VERSION 5.8 ;
BUSBITCHARS "[]" ;
DIVIDERCHAR "/" ;
UNITS
    DATABASE MICRONS 1000 ;
END UNITS

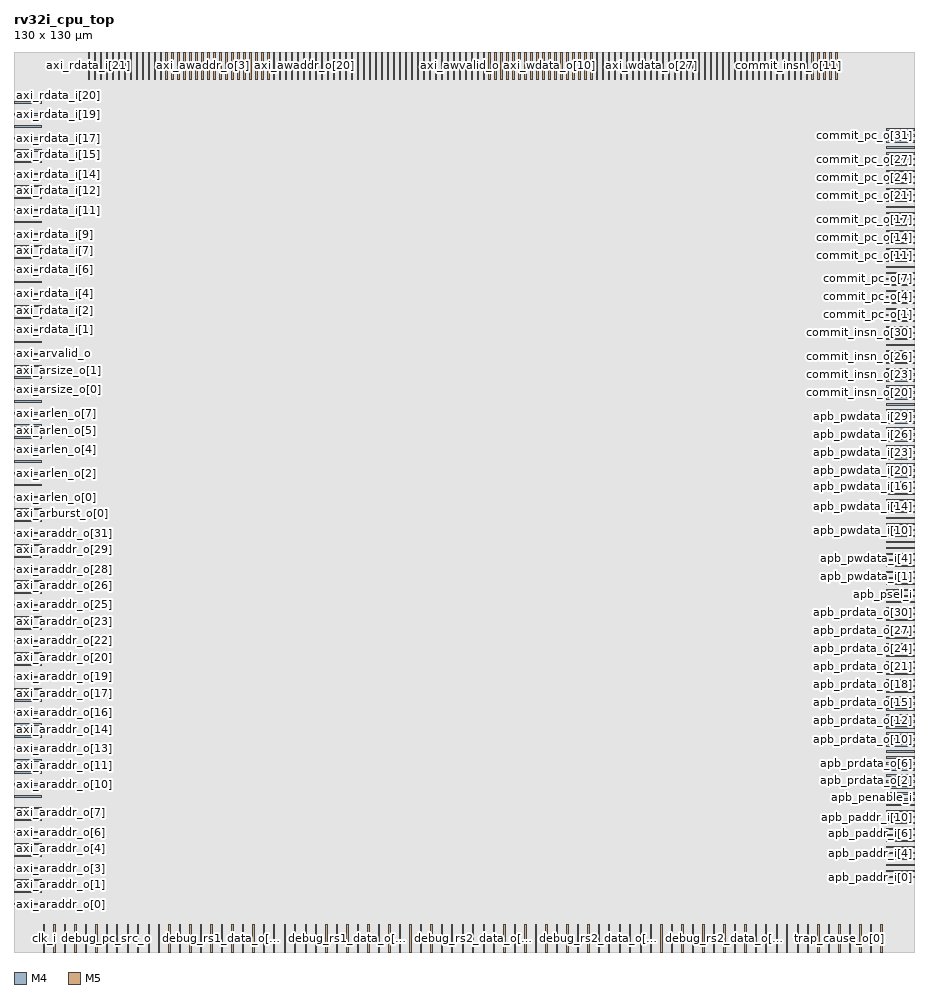
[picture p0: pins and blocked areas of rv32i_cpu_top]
MACRO rv32i_cpu_top
  FOREIGN rv32i_cpu_top 0 0 ;
  CLASS BLOCK ;
  SIZE 130 BY 130 ;
  PIN VDD
    USE POWER ;
    DIRECTION INOUT ;
  END VDD
  PIN VSS
    USE GROUND ;
    DIRECTION INOUT ;
  END VSS
  PIN apb_paddr_i[0]
    DIRECTION INPUT ;
    USE SIGNAL ;
    PORT
      LAYER M4 ;
        RECT  126 10.722 130 10.914 ;
    END
  END apb_paddr_i[0]
  PIN apb_paddr_i[10]
    DIRECTION INPUT ;
    USE SIGNAL ;
    PORT
      LAYER M4 ;
        RECT  126 19.362 130 19.554 ;
    END
  END apb_paddr_i[10]
  PIN apb_paddr_i[11]
    DIRECTION INPUT ;
    USE SIGNAL ;
    PORT
      LAYER M4 ;
        RECT  126 20.226 130 20.418 ;
    END
  END apb_paddr_i[11]
  PIN apb_paddr_i[1]
    DIRECTION INPUT ;
    USE SIGNAL ;
    PORT
      LAYER M4 ;
        RECT  126 11.586 130 11.778 ;
    END
  END apb_paddr_i[1]
  PIN apb_paddr_i[2]
    DIRECTION INPUT ;
    USE SIGNAL ;
    PORT
      LAYER M4 ;
        RECT  126 12.45 130 12.642 ;
    END
  END apb_paddr_i[2]
  PIN apb_paddr_i[3]
    DIRECTION INPUT ;
    USE SIGNAL ;
    PORT
      LAYER M4 ;
        RECT  126 13.314 130 13.506 ;
    END
  END apb_paddr_i[3]
  PIN apb_paddr_i[4]
    DIRECTION INPUT ;
    USE SIGNAL ;
    PORT
      LAYER M4 ;
        RECT  126 14.178 130 14.37 ;
    END
  END apb_paddr_i[4]
  PIN apb_paddr_i[5]
    DIRECTION INPUT ;
    USE SIGNAL ;
    PORT
      LAYER M4 ;
        RECT  126 15.042 130 15.234 ;
    END
  END apb_paddr_i[5]
  PIN apb_paddr_i[6]
    DIRECTION INPUT ;
    USE SIGNAL ;
    PORT
      LAYER M4 ;
        RECT  126 15.906 130 16.098 ;
    END
  END apb_paddr_i[6]
  PIN apb_paddr_i[7]
    DIRECTION INPUT ;
    USE SIGNAL ;
    PORT
      LAYER M4 ;
        RECT  126 16.77 130 16.962 ;
    END
  END apb_paddr_i[7]
  PIN apb_paddr_i[8]
    DIRECTION INPUT ;
    USE SIGNAL ;
    PORT
      LAYER M4 ;
        RECT  126 17.634 130 17.826 ;
    END
  END apb_paddr_i[8]
  PIN apb_paddr_i[9]
    DIRECTION INPUT ;
    USE SIGNAL ;
    PORT
      LAYER M4 ;
        RECT  126 18.498 130 18.69 ;
    END
  END apb_paddr_i[9]
  PIN apb_penable_i
    DIRECTION INPUT ;
    USE SIGNAL ;
    PORT
      LAYER M4 ;
        RECT  126 21.09 130 21.282 ;
    END
  END apb_penable_i
  PIN apb_prdata_o[0]
    DIRECTION OUTPUT ;
    USE SIGNAL ;
    PORT
      LAYER M4 ;
        RECT  126 21.954 130 22.146 ;
    END
  END apb_prdata_o[0]
  PIN apb_prdata_o[10]
    DIRECTION OUTPUT ;
    USE SIGNAL ;
    PORT
      LAYER M4 ;
        RECT  126 30.594 130 30.786 ;
    END
  END apb_prdata_o[10]
  PIN apb_prdata_o[11]
    DIRECTION OUTPUT ;
    USE SIGNAL ;
    PORT
      LAYER M4 ;
        RECT  126 31.458 130 31.65 ;
    END
  END apb_prdata_o[11]
  PIN apb_prdata_o[12]
    DIRECTION OUTPUT ;
    USE SIGNAL ;
    PORT
      LAYER M4 ;
        RECT  126 32.322 130 32.514 ;
    END
  END apb_prdata_o[12]
  PIN apb_prdata_o[13]
    DIRECTION OUTPUT ;
    USE SIGNAL ;
    PORT
      LAYER M4 ;
        RECT  126 33.186 130 33.378 ;
    END
  END apb_prdata_o[13]
  PIN apb_prdata_o[14]
    DIRECTION OUTPUT ;
    USE SIGNAL ;
    PORT
      LAYER M4 ;
        RECT  126 34.05 130 34.242 ;
    END
  END apb_prdata_o[14]
  PIN apb_prdata_o[15]
    DIRECTION OUTPUT ;
    USE SIGNAL ;
    PORT
      LAYER M4 ;
        RECT  126 34.914 130 35.106 ;
    END
  END apb_prdata_o[15]
  PIN apb_prdata_o[16]
    DIRECTION OUTPUT ;
    USE SIGNAL ;
    PORT
      LAYER M4 ;
        RECT  126 35.778 130 35.97 ;
    END
  END apb_prdata_o[16]
  PIN apb_prdata_o[17]
    DIRECTION OUTPUT ;
    USE SIGNAL ;
    PORT
      LAYER M4 ;
        RECT  126 36.642 130 36.834 ;
    END
  END apb_prdata_o[17]
  PIN apb_prdata_o[18]
    DIRECTION OUTPUT ;
    USE SIGNAL ;
    PORT
      LAYER M4 ;
        RECT  126 37.506 130 37.698 ;
    END
  END apb_prdata_o[18]
  PIN apb_prdata_o[19]
    DIRECTION OUTPUT ;
    USE SIGNAL ;
    PORT
      LAYER M4 ;
        RECT  126 38.37 130 38.562 ;
    END
  END apb_prdata_o[19]
  PIN apb_prdata_o[1]
    DIRECTION OUTPUT ;
    USE SIGNAL ;
    PORT
      LAYER M4 ;
        RECT  126 22.818 130 23.01 ;
    END
  END apb_prdata_o[1]
  PIN apb_prdata_o[20]
    DIRECTION OUTPUT ;
    USE SIGNAL ;
    PORT
      LAYER M4 ;
        RECT  126 39.234 130 39.426 ;
    END
  END apb_prdata_o[20]
  PIN apb_prdata_o[21]
    DIRECTION OUTPUT ;
    USE SIGNAL ;
    PORT
      LAYER M4 ;
        RECT  126 40.098 130 40.29 ;
    END
  END apb_prdata_o[21]
  PIN apb_prdata_o[22]
    DIRECTION OUTPUT ;
    USE SIGNAL ;
    PORT
      LAYER M4 ;
        RECT  126 40.962 130 41.154 ;
    END
  END apb_prdata_o[22]
  PIN apb_prdata_o[23]
    DIRECTION OUTPUT ;
    USE SIGNAL ;
    PORT
      LAYER M4 ;
        RECT  126 41.826 130 42.018 ;
    END
  END apb_prdata_o[23]
  PIN apb_prdata_o[24]
    DIRECTION OUTPUT ;
    USE SIGNAL ;
    PORT
      LAYER M4 ;
        RECT  126 42.69 130 42.882 ;
    END
  END apb_prdata_o[24]
  PIN apb_prdata_o[25]
    DIRECTION OUTPUT ;
    USE SIGNAL ;
    PORT
      LAYER M4 ;
        RECT  126 43.554 130 43.746 ;
    END
  END apb_prdata_o[25]
  PIN apb_prdata_o[26]
    DIRECTION OUTPUT ;
    USE SIGNAL ;
    PORT
      LAYER M4 ;
        RECT  126 44.418 130 44.61 ;
    END
  END apb_prdata_o[26]
  PIN apb_prdata_o[27]
    DIRECTION OUTPUT ;
    USE SIGNAL ;
    PORT
      LAYER M4 ;
        RECT  126 45.282 130 45.474 ;
    END
  END apb_prdata_o[27]
  PIN apb_prdata_o[28]
    DIRECTION OUTPUT ;
    USE SIGNAL ;
    PORT
      LAYER M4 ;
        RECT  126 46.146 130 46.338 ;
    END
  END apb_prdata_o[28]
  PIN apb_prdata_o[29]
    DIRECTION OUTPUT ;
    USE SIGNAL ;
    PORT
      LAYER M4 ;
        RECT  126 47.01 130 47.202 ;
    END
  END apb_prdata_o[29]
  PIN apb_prdata_o[2]
    DIRECTION OUTPUT ;
    USE SIGNAL ;
    PORT
      LAYER M4 ;
        RECT  126 23.682 130 23.874 ;
    END
  END apb_prdata_o[2]
  PIN apb_prdata_o[30]
    DIRECTION OUTPUT ;
    USE SIGNAL ;
    PORT
      LAYER M4 ;
        RECT  126 47.874 130 48.066 ;
    END
  END apb_prdata_o[30]
  PIN apb_prdata_o[31]
    DIRECTION OUTPUT ;
    USE SIGNAL ;
    PORT
      LAYER M4 ;
        RECT  126 48.738 130 48.93 ;
    END
  END apb_prdata_o[31]
  PIN apb_prdata_o[3]
    DIRECTION OUTPUT ;
    USE SIGNAL ;
    PORT
      LAYER M4 ;
        RECT  126 24.546 130 24.738 ;
    END
  END apb_prdata_o[3]
  PIN apb_prdata_o[4]
    DIRECTION OUTPUT ;
    USE SIGNAL ;
    PORT
      LAYER M4 ;
        RECT  126 25.41 130 25.602 ;
    END
  END apb_prdata_o[4]
  PIN apb_prdata_o[5]
    DIRECTION OUTPUT ;
    USE SIGNAL ;
    PORT
      LAYER M4 ;
        RECT  126 26.274 130 26.466 ;
    END
  END apb_prdata_o[5]
  PIN apb_prdata_o[6]
    DIRECTION OUTPUT ;
    USE SIGNAL ;
    PORT
      LAYER M4 ;
        RECT  126 27.138 130 27.33 ;
    END
  END apb_prdata_o[6]
  PIN apb_prdata_o[7]
    DIRECTION OUTPUT ;
    USE SIGNAL ;
    PORT
      LAYER M4 ;
        RECT  126 28.002 130 28.194 ;
    END
  END apb_prdata_o[7]
  PIN apb_prdata_o[8]
    DIRECTION OUTPUT ;
    USE SIGNAL ;
    PORT
      LAYER M4 ;
        RECT  126 28.866 130 29.058 ;
    END
  END apb_prdata_o[8]
  PIN apb_prdata_o[9]
    DIRECTION OUTPUT ;
    USE SIGNAL ;
    PORT
      LAYER M4 ;
        RECT  126 29.73 130 29.922 ;
    END
  END apb_prdata_o[9]
  PIN apb_pready_o
    DIRECTION OUTPUT ;
    USE SIGNAL ;
    PORT
      LAYER M4 ;
        RECT  126 49.602 130 49.794 ;
    END
  END apb_pready_o
  PIN apb_psel_i
    DIRECTION INPUT ;
    USE SIGNAL ;
    PORT
      LAYER M4 ;
        RECT  126 50.466 130 50.658 ;
    END
  END apb_psel_i
  PIN apb_pslverr_o
    DIRECTION OUTPUT ;
    USE SIGNAL ;
    PORT
      LAYER M4 ;
        RECT  126 51.33 130 51.522 ;
    END
  END apb_pslverr_o
  PIN apb_pwdata_i[0]
    DIRECTION INPUT ;
    USE SIGNAL ;
    PORT
      LAYER M4 ;
        RECT  126 52.194 130 52.386 ;
    END
  END apb_pwdata_i[0]
  PIN apb_pwdata_i[10]
    DIRECTION INPUT ;
    USE SIGNAL ;
    PORT
      LAYER M4 ;
        RECT  126 60.834 130 61.026 ;
    END
  END apb_pwdata_i[10]
  PIN apb_pwdata_i[11]
    DIRECTION INPUT ;
    USE SIGNAL ;
    PORT
      LAYER M4 ;
        RECT  126 61.698 130 61.89 ;
    END
  END apb_pwdata_i[11]
  PIN apb_pwdata_i[12]
    DIRECTION INPUT ;
    USE SIGNAL ;
    PORT
      LAYER M4 ;
        RECT  126 62.562 130 62.754 ;
    END
  END apb_pwdata_i[12]
  PIN apb_pwdata_i[13]
    DIRECTION INPUT ;
    USE SIGNAL ;
    PORT
      LAYER M4 ;
        RECT  126 63.426 130 63.618 ;
    END
  END apb_pwdata_i[13]
  PIN apb_pwdata_i[14]
    DIRECTION INPUT ;
    USE SIGNAL ;
    PORT
      LAYER M4 ;
        RECT  126 64.29 130 64.482 ;
    END
  END apb_pwdata_i[14]
  PIN apb_pwdata_i[15]
    DIRECTION INPUT ;
    USE SIGNAL ;
    PORT
      LAYER M4 ;
        RECT  126 65.154 130 65.346 ;
    END
  END apb_pwdata_i[15]
  PIN apb_pwdata_i[16]
    DIRECTION INPUT ;
    USE SIGNAL ;
    PORT
      LAYER M4 ;
        RECT  126 66.018 130 66.21 ;
    END
  END apb_pwdata_i[16]
  PIN apb_pwdata_i[17]
    DIRECTION INPUT ;
    USE SIGNAL ;
    PORT
      LAYER M4 ;
        RECT  126 66.882 130 67.074 ;
    END
  END apb_pwdata_i[17]
  PIN apb_pwdata_i[18]
    DIRECTION INPUT ;
    USE SIGNAL ;
    PORT
      LAYER M4 ;
        RECT  126 67.746 130 67.938 ;
    END
  END apb_pwdata_i[18]
  PIN apb_pwdata_i[19]
    DIRECTION INPUT ;
    USE SIGNAL ;
    PORT
      LAYER M4 ;
        RECT  126 68.61 130 68.802 ;
    END
  END apb_pwdata_i[19]
  PIN apb_pwdata_i[1]
    DIRECTION INPUT ;
    USE SIGNAL ;
    PORT
      LAYER M4 ;
        RECT  126 53.058 130 53.25 ;
    END
  END apb_pwdata_i[1]
  PIN apb_pwdata_i[20]
    DIRECTION INPUT ;
    USE SIGNAL ;
    PORT
      LAYER M4 ;
        RECT  126 69.474 130 69.666 ;
    END
  END apb_pwdata_i[20]
  PIN apb_pwdata_i[21]
    DIRECTION INPUT ;
    USE SIGNAL ;
    PORT
      LAYER M4 ;
        RECT  126 70.338 130 70.53 ;
    END
  END apb_pwdata_i[21]
  PIN apb_pwdata_i[22]
    DIRECTION INPUT ;
    USE SIGNAL ;
    PORT
      LAYER M4 ;
        RECT  126 71.202 130 71.394 ;
    END
  END apb_pwdata_i[22]
  PIN apb_pwdata_i[23]
    DIRECTION INPUT ;
    USE SIGNAL ;
    PORT
      LAYER M4 ;
        RECT  126 72.066 130 72.258 ;
    END
  END apb_pwdata_i[23]
  PIN apb_pwdata_i[24]
    DIRECTION INPUT ;
    USE SIGNAL ;
    PORT
      LAYER M4 ;
        RECT  126 72.93 130 73.122 ;
    END
  END apb_pwdata_i[24]
  PIN apb_pwdata_i[25]
    DIRECTION INPUT ;
    USE SIGNAL ;
    PORT
      LAYER M4 ;
        RECT  126 73.794 130 73.986 ;
    END
  END apb_pwdata_i[25]
  PIN apb_pwdata_i[26]
    DIRECTION INPUT ;
    USE SIGNAL ;
    PORT
      LAYER M4 ;
        RECT  126 74.658 130 74.85 ;
    END
  END apb_pwdata_i[26]
  PIN apb_pwdata_i[27]
    DIRECTION INPUT ;
    USE SIGNAL ;
    PORT
      LAYER M4 ;
        RECT  126 75.522 130 75.714 ;
    END
  END apb_pwdata_i[27]
  PIN apb_pwdata_i[28]
    DIRECTION INPUT ;
    USE SIGNAL ;
    PORT
      LAYER M4 ;
        RECT  126 76.386 130 76.578 ;
    END
  END apb_pwdata_i[28]
  PIN apb_pwdata_i[29]
    DIRECTION INPUT ;
    USE SIGNAL ;
    PORT
      LAYER M4 ;
        RECT  126 77.25 130 77.442 ;
    END
  END apb_pwdata_i[29]
  PIN apb_pwdata_i[2]
    DIRECTION INPUT ;
    USE SIGNAL ;
    PORT
      LAYER M4 ;
        RECT  126 53.922 130 54.114 ;
    END
  END apb_pwdata_i[2]
  PIN apb_pwdata_i[30]
    DIRECTION INPUT ;
    USE SIGNAL ;
    PORT
      LAYER M4 ;
        RECT  126 78.114 130 78.306 ;
    END
  END apb_pwdata_i[30]
  PIN apb_pwdata_i[31]
    DIRECTION INPUT ;
    USE SIGNAL ;
    PORT
      LAYER M4 ;
        RECT  126 78.978 130 79.17 ;
    END
  END apb_pwdata_i[31]
  PIN apb_pwdata_i[3]
    DIRECTION INPUT ;
    USE SIGNAL ;
    PORT
      LAYER M4 ;
        RECT  126 54.786 130 54.978 ;
    END
  END apb_pwdata_i[3]
  PIN apb_pwdata_i[4]
    DIRECTION INPUT ;
    USE SIGNAL ;
    PORT
      LAYER M4 ;
        RECT  126 55.65 130 55.842 ;
    END
  END apb_pwdata_i[4]
  PIN apb_pwdata_i[5]
    DIRECTION INPUT ;
    USE SIGNAL ;
    PORT
      LAYER M4 ;
        RECT  126 56.514 130 56.706 ;
    END
  END apb_pwdata_i[5]
  PIN apb_pwdata_i[6]
    DIRECTION INPUT ;
    USE SIGNAL ;
    PORT
      LAYER M4 ;
        RECT  126 57.378 130 57.57 ;
    END
  END apb_pwdata_i[6]
  PIN apb_pwdata_i[7]
    DIRECTION INPUT ;
    USE SIGNAL ;
    PORT
      LAYER M4 ;
        RECT  126 58.242 130 58.434 ;
    END
  END apb_pwdata_i[7]
  PIN apb_pwdata_i[8]
    DIRECTION INPUT ;
    USE SIGNAL ;
    PORT
      LAYER M4 ;
        RECT  126 59.106 130 59.298 ;
    END
  END apb_pwdata_i[8]
  PIN apb_pwdata_i[9]
    DIRECTION INPUT ;
    USE SIGNAL ;
    PORT
      LAYER M4 ;
        RECT  126 59.97 130 60.162 ;
    END
  END apb_pwdata_i[9]
  PIN apb_pwrite_i
    DIRECTION INPUT ;
    USE SIGNAL ;
    PORT
      LAYER M4 ;
        RECT  126 79.842 130 80.034 ;
    END
  END apb_pwrite_i
  PIN axi_araddr_o[0]
    DIRECTION OUTPUT ;
    USE SIGNAL ;
    PORT
      LAYER M4 ;
        RECT  0 6.834 4 7.026 ;
    END
  END axi_araddr_o[0]
  PIN axi_araddr_o[10]
    DIRECTION OUTPUT ;
    USE SIGNAL ;
    PORT
      LAYER M4 ;
        RECT  0 24.114 4 24.306 ;
    END
  END axi_araddr_o[10]
  PIN axi_araddr_o[11]
    DIRECTION OUTPUT ;
    USE SIGNAL ;
    PORT
      LAYER M4 ;
        RECT  0 25.842 4 26.034 ;
    END
  END axi_araddr_o[11]
  PIN axi_araddr_o[12]
    DIRECTION OUTPUT ;
    USE SIGNAL ;
    PORT
      LAYER M4 ;
        RECT  0 27.57 4 27.762 ;
    END
  END axi_araddr_o[12]
  PIN axi_araddr_o[13]
    DIRECTION OUTPUT ;
    USE SIGNAL ;
    PORT
      LAYER M4 ;
        RECT  0 29.298 4 29.49 ;
    END
  END axi_araddr_o[13]
  PIN axi_araddr_o[14]
    DIRECTION OUTPUT ;
    USE SIGNAL ;
    PORT
      LAYER M4 ;
        RECT  0 31.026 4 31.218 ;
    END
  END axi_araddr_o[14]
  PIN axi_araddr_o[15]
    DIRECTION OUTPUT ;
    USE SIGNAL ;
    PORT
      LAYER M4 ;
        RECT  0 32.754 4 32.946 ;
    END
  END axi_araddr_o[15]
  PIN axi_araddr_o[16]
    DIRECTION OUTPUT ;
    USE SIGNAL ;
    PORT
      LAYER M4 ;
        RECT  0 34.482 4 34.674 ;
    END
  END axi_araddr_o[16]
  PIN axi_araddr_o[17]
    DIRECTION OUTPUT ;
    USE SIGNAL ;
    PORT
      LAYER M4 ;
        RECT  0 36.21 4 36.402 ;
    END
  END axi_araddr_o[17]
  PIN axi_araddr_o[18]
    DIRECTION OUTPUT ;
    USE SIGNAL ;
    PORT
      LAYER M4 ;
        RECT  0 37.938 4 38.13 ;
    END
  END axi_araddr_o[18]
  PIN axi_araddr_o[19]
    DIRECTION OUTPUT ;
    USE SIGNAL ;
    PORT
      LAYER M4 ;
        RECT  0 39.666 4 39.858 ;
    END
  END axi_araddr_o[19]
  PIN axi_araddr_o[1]
    DIRECTION OUTPUT ;
    USE SIGNAL ;
    PORT
      LAYER M4 ;
        RECT  0 8.562 4 8.754 ;
    END
  END axi_araddr_o[1]
  PIN axi_araddr_o[20]
    DIRECTION OUTPUT ;
    USE SIGNAL ;
    PORT
      LAYER M4 ;
        RECT  0 41.394 4 41.586 ;
    END
  END axi_araddr_o[20]
  PIN axi_araddr_o[21]
    DIRECTION OUTPUT ;
    USE SIGNAL ;
    PORT
      LAYER M4 ;
        RECT  0 43.122 4 43.314 ;
    END
  END axi_araddr_o[21]
  PIN axi_araddr_o[22]
    DIRECTION OUTPUT ;
    USE SIGNAL ;
    PORT
      LAYER M4 ;
        RECT  0 44.85 4 45.042 ;
    END
  END axi_araddr_o[22]
  PIN axi_araddr_o[23]
    DIRECTION OUTPUT ;
    USE SIGNAL ;
    PORT
      LAYER M4 ;
        RECT  0 46.578 4 46.77 ;
    END
  END axi_araddr_o[23]
  PIN axi_araddr_o[24]
    DIRECTION OUTPUT ;
    USE SIGNAL ;
    PORT
      LAYER M4 ;
        RECT  0 48.306 4 48.498 ;
    END
  END axi_araddr_o[24]
  PIN axi_araddr_o[25]
    DIRECTION OUTPUT ;
    USE SIGNAL ;
    PORT
      LAYER M4 ;
        RECT  0 50.034 4 50.226 ;
    END
  END axi_araddr_o[25]
  PIN axi_araddr_o[26]
    DIRECTION OUTPUT ;
    USE SIGNAL ;
    PORT
      LAYER M4 ;
        RECT  0 51.762 4 51.954 ;
    END
  END axi_araddr_o[26]
  PIN axi_araddr_o[27]
    DIRECTION OUTPUT ;
    USE SIGNAL ;
    PORT
      LAYER M4 ;
        RECT  0 53.49 4 53.682 ;
    END
  END axi_araddr_o[27]
  PIN axi_araddr_o[28]
    DIRECTION OUTPUT ;
    USE SIGNAL ;
    PORT
      LAYER M4 ;
        RECT  0 55.218 4 55.41 ;
    END
  END axi_araddr_o[28]
  PIN axi_araddr_o[29]
    DIRECTION OUTPUT ;
    USE SIGNAL ;
    PORT
      LAYER M4 ;
        RECT  0 56.946 4 57.138 ;
    END
  END axi_araddr_o[29]
  PIN axi_araddr_o[2]
    DIRECTION OUTPUT ;
    USE SIGNAL ;
    PORT
      LAYER M4 ;
        RECT  0 10.29 4 10.482 ;
    END
  END axi_araddr_o[2]
  PIN axi_araddr_o[30]
    DIRECTION OUTPUT ;
    USE SIGNAL ;
    PORT
      LAYER M4 ;
        RECT  0 58.674 4 58.866 ;
    END
  END axi_araddr_o[30]
  PIN axi_araddr_o[31]
    DIRECTION OUTPUT ;
    USE SIGNAL ;
    PORT
      LAYER M4 ;
        RECT  0 60.402 4 60.594 ;
    END
  END axi_araddr_o[31]
  PIN axi_araddr_o[3]
    DIRECTION OUTPUT ;
    USE SIGNAL ;
    PORT
      LAYER M4 ;
        RECT  0 12.018 4 12.21 ;
    END
  END axi_araddr_o[3]
  PIN axi_araddr_o[4]
    DIRECTION OUTPUT ;
    USE SIGNAL ;
    PORT
      LAYER M4 ;
        RECT  0 13.746 4 13.938 ;
    END
  END axi_araddr_o[4]
  PIN axi_araddr_o[5]
    DIRECTION OUTPUT ;
    USE SIGNAL ;
    PORT
      LAYER M4 ;
        RECT  0 15.474 4 15.666 ;
    END
  END axi_araddr_o[5]
  PIN axi_araddr_o[6]
    DIRECTION OUTPUT ;
    USE SIGNAL ;
    PORT
      LAYER M4 ;
        RECT  0 17.202 4 17.394 ;
    END
  END axi_araddr_o[6]
  PIN axi_araddr_o[7]
    DIRECTION OUTPUT ;
    USE SIGNAL ;
    PORT
      LAYER M4 ;
        RECT  0 18.93 4 19.122 ;
    END
  END axi_araddr_o[7]
  PIN axi_araddr_o[8]
    DIRECTION OUTPUT ;
    USE SIGNAL ;
    PORT
      LAYER M4 ;
        RECT  0 20.658 4 20.85 ;
    END
  END axi_araddr_o[8]
  PIN axi_araddr_o[9]
    DIRECTION OUTPUT ;
    USE SIGNAL ;
    PORT
      LAYER M4 ;
        RECT  0 22.386 4 22.578 ;
    END
  END axi_araddr_o[9]
  PIN axi_arburst_o[0]
    DIRECTION OUTPUT ;
    USE SIGNAL ;
    PORT
      LAYER M4 ;
        RECT  0 62.13 4 62.322 ;
    END
  END axi_arburst_o[0]
  PIN axi_arburst_o[1]
    DIRECTION OUTPUT ;
    USE SIGNAL ;
    PORT
      LAYER M4 ;
        RECT  0 63.858 4 64.05 ;
    END
  END axi_arburst_o[1]
  PIN axi_arlen_o[0]
    DIRECTION OUTPUT ;
    USE SIGNAL ;
    PORT
      LAYER M4 ;
        RECT  0 65.586 4 65.778 ;
    END
  END axi_arlen_o[0]
  PIN axi_arlen_o[1]
    DIRECTION OUTPUT ;
    USE SIGNAL ;
    PORT
      LAYER M4 ;
        RECT  0 67.314 4 67.506 ;
    END
  END axi_arlen_o[1]
  PIN axi_arlen_o[2]
    DIRECTION OUTPUT ;
    USE SIGNAL ;
    PORT
      LAYER M4 ;
        RECT  0 69.042 4 69.234 ;
    END
  END axi_arlen_o[2]
  PIN axi_arlen_o[3]
    DIRECTION OUTPUT ;
    USE SIGNAL ;
    PORT
      LAYER M4 ;
        RECT  0 70.77 4 70.962 ;
    END
  END axi_arlen_o[3]
  PIN axi_arlen_o[4]
    DIRECTION OUTPUT ;
    USE SIGNAL ;
    PORT
      LAYER M4 ;
        RECT  0 72.498 4 72.69 ;
    END
  END axi_arlen_o[4]
  PIN axi_arlen_o[5]
    DIRECTION OUTPUT ;
    USE SIGNAL ;
    PORT
      LAYER M4 ;
        RECT  0 74.226 4 74.418 ;
    END
  END axi_arlen_o[5]
  PIN axi_arlen_o[6]
    DIRECTION OUTPUT ;
    USE SIGNAL ;
    PORT
      LAYER M4 ;
        RECT  0 75.954 4 76.146 ;
    END
  END axi_arlen_o[6]
  PIN axi_arlen_o[7]
    DIRECTION OUTPUT ;
    USE SIGNAL ;
    PORT
      LAYER M4 ;
        RECT  0 77.682 4 77.874 ;
    END
  END axi_arlen_o[7]
  PIN axi_arready_i
    DIRECTION INPUT ;
    USE SIGNAL ;
    PORT
      LAYER M4 ;
        RECT  0 79.41 4 79.602 ;
    END
  END axi_arready_i
  PIN axi_arsize_o[0]
    DIRECTION OUTPUT ;
    USE SIGNAL ;
    PORT
      LAYER M4 ;
        RECT  0 81.138 4 81.33 ;
    END
  END axi_arsize_o[0]
  PIN axi_arsize_o[1]
    DIRECTION OUTPUT ;
    USE SIGNAL ;
    PORT
      LAYER M4 ;
        RECT  0 82.866 4 83.058 ;
    END
  END axi_arsize_o[1]
  PIN axi_arsize_o[2]
    DIRECTION OUTPUT ;
    USE SIGNAL ;
    PORT
      LAYER M4 ;
        RECT  0 84.594 4 84.786 ;
    END
  END axi_arsize_o[2]
  PIN axi_arvalid_o
    DIRECTION OUTPUT ;
    USE SIGNAL ;
    PORT
      LAYER M4 ;
        RECT  0 86.322 4 86.514 ;
    END
  END axi_arvalid_o
  PIN axi_awaddr_o[0]
    DIRECTION OUTPUT ;
    USE SIGNAL ;
    PORT
      LAYER M5 ;
        RECT  24.546 126 24.738 130 ;
    END
  END axi_awaddr_o[0]
  PIN axi_awaddr_o[10]
    DIRECTION OUTPUT ;
    USE SIGNAL ;
    PORT
      LAYER M5 ;
        RECT  33.186 126 33.378 130 ;
    END
  END axi_awaddr_o[10]
  PIN axi_awaddr_o[11]
    DIRECTION OUTPUT ;
    USE SIGNAL ;
    PORT
      LAYER M5 ;
        RECT  34.05 126 34.242 130 ;
    END
  END axi_awaddr_o[11]
  PIN axi_awaddr_o[12]
    DIRECTION OUTPUT ;
    USE SIGNAL ;
    PORT
      LAYER M5 ;
        RECT  34.914 126 35.106 130 ;
    END
  END axi_awaddr_o[12]
  PIN axi_awaddr_o[13]
    DIRECTION OUTPUT ;
    USE SIGNAL ;
    PORT
      LAYER M5 ;
        RECT  35.778 126 35.97 130 ;
    END
  END axi_awaddr_o[13]
  PIN axi_awaddr_o[14]
    DIRECTION OUTPUT ;
    USE SIGNAL ;
    PORT
      LAYER M5 ;
        RECT  36.642 126 36.834 130 ;
    END
  END axi_awaddr_o[14]
  PIN axi_awaddr_o[15]
    DIRECTION OUTPUT ;
    USE SIGNAL ;
    PORT
      LAYER M5 ;
        RECT  37.506 126 37.698 130 ;
    END
  END axi_awaddr_o[15]
  PIN axi_awaddr_o[16]
    DIRECTION OUTPUT ;
    USE SIGNAL ;
    PORT
      LAYER M5 ;
        RECT  38.37 126 38.562 130 ;
    END
  END axi_awaddr_o[16]
  PIN axi_awaddr_o[17]
    DIRECTION OUTPUT ;
    USE SIGNAL ;
    PORT
      LAYER M5 ;
        RECT  39.234 126 39.426 130 ;
    END
  END axi_awaddr_o[17]
  PIN axi_awaddr_o[18]
    DIRECTION OUTPUT ;
    USE SIGNAL ;
    PORT
      LAYER M5 ;
        RECT  40.098 126 40.29 130 ;
    END
  END axi_awaddr_o[18]
  PIN axi_awaddr_o[19]
    DIRECTION OUTPUT ;
    USE SIGNAL ;
    PORT
      LAYER M5 ;
        RECT  40.962 126 41.154 130 ;
    END
  END axi_awaddr_o[19]
  PIN axi_awaddr_o[1]
    DIRECTION OUTPUT ;
    USE SIGNAL ;
    PORT
      LAYER M5 ;
        RECT  25.41 126 25.602 130 ;
    END
  END axi_awaddr_o[1]
  PIN axi_awaddr_o[20]
    DIRECTION OUTPUT ;
    USE SIGNAL ;
    PORT
      LAYER M5 ;
        RECT  41.826 126 42.018 130 ;
    END
  END axi_awaddr_o[20]
  PIN axi_awaddr_o[21]
    DIRECTION OUTPUT ;
    USE SIGNAL ;
    PORT
      LAYER M5 ;
        RECT  42.69 126 42.882 130 ;
    END
  END axi_awaddr_o[21]
  PIN axi_awaddr_o[22]
    DIRECTION OUTPUT ;
    USE SIGNAL ;
    PORT
      LAYER M5 ;
        RECT  43.554 126 43.746 130 ;
    END
  END axi_awaddr_o[22]
  PIN axi_awaddr_o[23]
    DIRECTION OUTPUT ;
    USE SIGNAL ;
    PORT
      LAYER M5 ;
        RECT  44.418 126 44.61 130 ;
    END
  END axi_awaddr_o[23]
  PIN axi_awaddr_o[24]
    DIRECTION OUTPUT ;
    USE SIGNAL ;
    PORT
      LAYER M5 ;
        RECT  45.282 126 45.474 130 ;
    END
  END axi_awaddr_o[24]
  PIN axi_awaddr_o[25]
    DIRECTION OUTPUT ;
    USE SIGNAL ;
    PORT
      LAYER M5 ;
        RECT  46.146 126 46.338 130 ;
    END
  END axi_awaddr_o[25]
  PIN axi_awaddr_o[26]
    DIRECTION OUTPUT ;
    USE SIGNAL ;
    PORT
      LAYER M5 ;
        RECT  47.01 126 47.202 130 ;
    END
  END axi_awaddr_o[26]
  PIN axi_awaddr_o[27]
    DIRECTION OUTPUT ;
    USE SIGNAL ;
    PORT
      LAYER M5 ;
        RECT  47.874 126 48.066 130 ;
    END
  END axi_awaddr_o[27]
  PIN axi_awaddr_o[28]
    DIRECTION OUTPUT ;
    USE SIGNAL ;
    PORT
      LAYER M5 ;
        RECT  48.738 126 48.93 130 ;
    END
  END axi_awaddr_o[28]
  PIN axi_awaddr_o[29]
    DIRECTION OUTPUT ;
    USE SIGNAL ;
    PORT
      LAYER M5 ;
        RECT  49.602 126 49.794 130 ;
    END
  END axi_awaddr_o[29]
  PIN axi_awaddr_o[2]
    DIRECTION OUTPUT ;
    USE SIGNAL ;
    PORT
      LAYER M5 ;
        RECT  26.274 126 26.466 130 ;
    END
  END axi_awaddr_o[2]
  PIN axi_awaddr_o[30]
    DIRECTION OUTPUT ;
    USE SIGNAL ;
    PORT
      LAYER M5 ;
        RECT  50.466 126 50.658 130 ;
    END
  END axi_awaddr_o[30]
  PIN axi_awaddr_o[31]
    DIRECTION OUTPUT ;
    USE SIGNAL ;
    PORT
      LAYER M5 ;
        RECT  51.33 126 51.522 130 ;
    END
  END axi_awaddr_o[31]
  PIN axi_awaddr_o[3]
    DIRECTION OUTPUT ;
    USE SIGNAL ;
    PORT
      LAYER M5 ;
        RECT  27.138 126 27.33 130 ;
    END
  END axi_awaddr_o[3]
  PIN axi_awaddr_o[4]
    DIRECTION OUTPUT ;
    USE SIGNAL ;
    PORT
      LAYER M5 ;
        RECT  28.002 126 28.194 130 ;
    END
  END axi_awaddr_o[4]
  PIN axi_awaddr_o[5]
    DIRECTION OUTPUT ;
    USE SIGNAL ;
    PORT
      LAYER M5 ;
        RECT  28.866 126 29.058 130 ;
    END
  END axi_awaddr_o[5]
  PIN axi_awaddr_o[6]
    DIRECTION OUTPUT ;
    USE SIGNAL ;
    PORT
      LAYER M5 ;
        RECT  29.73 126 29.922 130 ;
    END
  END axi_awaddr_o[6]
  PIN axi_awaddr_o[7]
    DIRECTION OUTPUT ;
    USE SIGNAL ;
    PORT
      LAYER M5 ;
        RECT  30.594 126 30.786 130 ;
    END
  END axi_awaddr_o[7]
  PIN axi_awaddr_o[8]
    DIRECTION OUTPUT ;
    USE SIGNAL ;
    PORT
      LAYER M5 ;
        RECT  31.458 126 31.65 130 ;
    END
  END axi_awaddr_o[8]
  PIN axi_awaddr_o[9]
    DIRECTION OUTPUT ;
    USE SIGNAL ;
    PORT
      LAYER M5 ;
        RECT  32.322 126 32.514 130 ;
    END
  END axi_awaddr_o[9]
  PIN axi_awburst_o[0]
    DIRECTION OUTPUT ;
    USE SIGNAL ;
    PORT
      LAYER M5 ;
        RECT  52.194 126 52.386 130 ;
    END
  END axi_awburst_o[0]
  PIN axi_awburst_o[1]
    DIRECTION OUTPUT ;
    USE SIGNAL ;
    PORT
      LAYER M5 ;
        RECT  53.058 126 53.25 130 ;
    END
  END axi_awburst_o[1]
  PIN axi_awlen_o[0]
    DIRECTION OUTPUT ;
    USE SIGNAL ;
    PORT
      LAYER M5 ;
        RECT  53.922 126 54.114 130 ;
    END
  END axi_awlen_o[0]
  PIN axi_awlen_o[1]
    DIRECTION OUTPUT ;
    USE SIGNAL ;
    PORT
      LAYER M5 ;
        RECT  54.786 126 54.978 130 ;
    END
  END axi_awlen_o[1]
  PIN axi_awlen_o[2]
    DIRECTION OUTPUT ;
    USE SIGNAL ;
    PORT
      LAYER M5 ;
        RECT  55.65 126 55.842 130 ;
    END
  END axi_awlen_o[2]
  PIN axi_awlen_o[3]
    DIRECTION OUTPUT ;
    USE SIGNAL ;
    PORT
      LAYER M5 ;
        RECT  56.514 126 56.706 130 ;
    END
  END axi_awlen_o[3]
  PIN axi_awlen_o[4]
    DIRECTION OUTPUT ;
    USE SIGNAL ;
    PORT
      LAYER M5 ;
        RECT  57.378 126 57.57 130 ;
    END
  END axi_awlen_o[4]
  PIN axi_awlen_o[5]
    DIRECTION OUTPUT ;
    USE SIGNAL ;
    PORT
      LAYER M5 ;
        RECT  58.242 126 58.434 130 ;
    END
  END axi_awlen_o[5]
  PIN axi_awlen_o[6]
    DIRECTION OUTPUT ;
    USE SIGNAL ;
    PORT
      LAYER M5 ;
        RECT  59.106 126 59.298 130 ;
    END
  END axi_awlen_o[6]
  PIN axi_awlen_o[7]
    DIRECTION OUTPUT ;
    USE SIGNAL ;
    PORT
      LAYER M5 ;
        RECT  59.97 126 60.162 130 ;
    END
  END axi_awlen_o[7]
  PIN axi_awready_i
    DIRECTION INPUT ;
    USE SIGNAL ;
    PORT
      LAYER M5 ;
        RECT  60.834 126 61.026 130 ;
    END
  END axi_awready_i
  PIN axi_awsize_o[0]
    DIRECTION OUTPUT ;
    USE SIGNAL ;
    PORT
      LAYER M5 ;
        RECT  61.698 126 61.89 130 ;
    END
  END axi_awsize_o[0]
  PIN axi_awsize_o[1]
    DIRECTION OUTPUT ;
    USE SIGNAL ;
    PORT
      LAYER M5 ;
        RECT  62.562 126 62.754 130 ;
    END
  END axi_awsize_o[1]
  PIN axi_awsize_o[2]
    DIRECTION OUTPUT ;
    USE SIGNAL ;
    PORT
      LAYER M5 ;
        RECT  63.426 126 63.618 130 ;
    END
  END axi_awsize_o[2]
  PIN axi_awvalid_o
    DIRECTION OUTPUT ;
    USE SIGNAL ;
    PORT
      LAYER M5 ;
        RECT  64.29 126 64.482 130 ;
    END
  END axi_awvalid_o
  PIN axi_bready_o
    DIRECTION OUTPUT ;
    USE SIGNAL ;
    PORT
      LAYER M5 ;
        RECT  65.154 126 65.346 130 ;
    END
  END axi_bready_o
  PIN axi_bresp_i[0]
    DIRECTION INPUT ;
    USE SIGNAL ;
    PORT
      LAYER M5 ;
        RECT  66.018 126 66.21 130 ;
    END
  END axi_bresp_i[0]
  PIN axi_bresp_i[1]
    DIRECTION INPUT ;
    USE SIGNAL ;
    PORT
      LAYER M5 ;
        RECT  66.882 126 67.074 130 ;
    END
  END axi_bresp_i[1]
  PIN axi_bvalid_i
    DIRECTION INPUT ;
    USE SIGNAL ;
    PORT
      LAYER M5 ;
        RECT  67.746 126 67.938 130 ;
    END
  END axi_bvalid_i
  PIN axi_rdata_i[0]
    DIRECTION INPUT ;
    USE SIGNAL ;
    PORT
      LAYER M4 ;
        RECT  0 88.05 4 88.242 ;
    END
  END axi_rdata_i[0]
  PIN axi_rdata_i[10]
    DIRECTION INPUT ;
    USE SIGNAL ;
    PORT
      LAYER M4 ;
        RECT  0 105.33 4 105.522 ;
    END
  END axi_rdata_i[10]
  PIN axi_rdata_i[11]
    DIRECTION INPUT ;
    USE SIGNAL ;
    PORT
      LAYER M4 ;
        RECT  0 107.058 4 107.25 ;
    END
  END axi_rdata_i[11]
  PIN axi_rdata_i[12]
    DIRECTION INPUT ;
    USE SIGNAL ;
    PORT
      LAYER M4 ;
        RECT  0 108.786 4 108.978 ;
    END
  END axi_rdata_i[12]
  PIN axi_rdata_i[13]
    DIRECTION INPUT ;
    USE SIGNAL ;
    PORT
      LAYER M4 ;
        RECT  0 110.514 4 110.706 ;
    END
  END axi_rdata_i[13]
  PIN axi_rdata_i[14]
    DIRECTION INPUT ;
    USE SIGNAL ;
    PORT
      LAYER M4 ;
        RECT  0 112.242 4 112.434 ;
    END
  END axi_rdata_i[14]
  PIN axi_rdata_i[15]
    DIRECTION INPUT ;
    USE SIGNAL ;
    PORT
      LAYER M4 ;
        RECT  0 113.97 4 114.162 ;
    END
  END axi_rdata_i[15]
  PIN axi_rdata_i[16]
    DIRECTION INPUT ;
    USE SIGNAL ;
    PORT
      LAYER M4 ;
        RECT  0 115.698 4 115.89 ;
    END
  END axi_rdata_i[16]
  PIN axi_rdata_i[17]
    DIRECTION INPUT ;
    USE SIGNAL ;
    PORT
      LAYER M4 ;
        RECT  0 117.426 4 117.618 ;
    END
  END axi_rdata_i[17]
  PIN axi_rdata_i[18]
    DIRECTION INPUT ;
    USE SIGNAL ;
    PORT
      LAYER M4 ;
        RECT  0 119.154 4 119.346 ;
    END
  END axi_rdata_i[18]
  PIN axi_rdata_i[19]
    DIRECTION INPUT ;
    USE SIGNAL ;
    PORT
      LAYER M4 ;
        RECT  0 120.882 4 121.074 ;
    END
  END axi_rdata_i[19]
  PIN axi_rdata_i[1]
    DIRECTION INPUT ;
    USE SIGNAL ;
    PORT
      LAYER M4 ;
        RECT  0 89.778 4 89.97 ;
    END
  END axi_rdata_i[1]
  PIN axi_rdata_i[20]
    DIRECTION INPUT ;
    USE SIGNAL ;
    PORT
      LAYER M4 ;
        RECT  0 122.61 4 122.802 ;
    END
  END axi_rdata_i[20]
  PIN axi_rdata_i[21]
    DIRECTION INPUT ;
    USE SIGNAL ;
    PORT
      LAYER M5 ;
        RECT  10.722 126 10.914 130 ;
    END
  END axi_rdata_i[21]
  PIN axi_rdata_i[22]
    DIRECTION INPUT ;
    USE SIGNAL ;
    PORT
      LAYER M5 ;
        RECT  11.586 126 11.778 130 ;
    END
  END axi_rdata_i[22]
  PIN axi_rdata_i[23]
    DIRECTION INPUT ;
    USE SIGNAL ;
    PORT
      LAYER M5 ;
        RECT  12.45 126 12.642 130 ;
    END
  END axi_rdata_i[23]
  PIN axi_rdata_i[24]
    DIRECTION INPUT ;
    USE SIGNAL ;
    PORT
      LAYER M5 ;
        RECT  13.314 126 13.506 130 ;
    END
  END axi_rdata_i[24]
  PIN axi_rdata_i[25]
    DIRECTION INPUT ;
    USE SIGNAL ;
    PORT
      LAYER M5 ;
        RECT  14.178 126 14.37 130 ;
    END
  END axi_rdata_i[25]
  PIN axi_rdata_i[26]
    DIRECTION INPUT ;
    USE SIGNAL ;
    PORT
      LAYER M5 ;
        RECT  15.042 126 15.234 130 ;
    END
  END axi_rdata_i[26]
  PIN axi_rdata_i[27]
    DIRECTION INPUT ;
    USE SIGNAL ;
    PORT
      LAYER M5 ;
        RECT  15.906 126 16.098 130 ;
    END
  END axi_rdata_i[27]
  PIN axi_rdata_i[28]
    DIRECTION INPUT ;
    USE SIGNAL ;
    PORT
      LAYER M5 ;
        RECT  16.77 126 16.962 130 ;
    END
  END axi_rdata_i[28]
  PIN axi_rdata_i[29]
    DIRECTION INPUT ;
    USE SIGNAL ;
    PORT
      LAYER M5 ;
        RECT  17.634 126 17.826 130 ;
    END
  END axi_rdata_i[29]
  PIN axi_rdata_i[2]
    DIRECTION INPUT ;
    USE SIGNAL ;
    PORT
      LAYER M4 ;
        RECT  0 91.506 4 91.698 ;
    END
  END axi_rdata_i[2]
  PIN axi_rdata_i[30]
    DIRECTION INPUT ;
    USE SIGNAL ;
    PORT
      LAYER M5 ;
        RECT  18.498 126 18.69 130 ;
    END
  END axi_rdata_i[30]
  PIN axi_rdata_i[31]
    DIRECTION INPUT ;
    USE SIGNAL ;
    PORT
      LAYER M5 ;
        RECT  19.362 126 19.554 130 ;
    END
  END axi_rdata_i[31]
  PIN axi_rdata_i[3]
    DIRECTION INPUT ;
    USE SIGNAL ;
    PORT
      LAYER M4 ;
        RECT  0 93.234 4 93.426 ;
    END
  END axi_rdata_i[3]
  PIN axi_rdata_i[4]
    DIRECTION INPUT ;
    USE SIGNAL ;
    PORT
      LAYER M4 ;
        RECT  0 94.962 4 95.154 ;
    END
  END axi_rdata_i[4]
  PIN axi_rdata_i[5]
    DIRECTION INPUT ;
    USE SIGNAL ;
    PORT
      LAYER M4 ;
        RECT  0 96.69 4 96.882 ;
    END
  END axi_rdata_i[5]
  PIN axi_rdata_i[6]
    DIRECTION INPUT ;
    USE SIGNAL ;
    PORT
      LAYER M4 ;
        RECT  0 98.418 4 98.61 ;
    END
  END axi_rdata_i[6]
  PIN axi_rdata_i[7]
    DIRECTION INPUT ;
    USE SIGNAL ;
    PORT
      LAYER M4 ;
        RECT  0 100.146 4 100.338 ;
    END
  END axi_rdata_i[7]
  PIN axi_rdata_i[8]
    DIRECTION INPUT ;
    USE SIGNAL ;
    PORT
      LAYER M4 ;
        RECT  0 101.874 4 102.066 ;
    END
  END axi_rdata_i[8]
  PIN axi_rdata_i[9]
    DIRECTION INPUT ;
    USE SIGNAL ;
    PORT
      LAYER M4 ;
        RECT  0 103.602 4 103.794 ;
    END
  END axi_rdata_i[9]
  PIN axi_rlast_i
    DIRECTION INPUT ;
    USE SIGNAL ;
    PORT
      LAYER M5 ;
        RECT  20.226 126 20.418 130 ;
    END
  END axi_rlast_i
  PIN axi_rready_o
    DIRECTION OUTPUT ;
    USE SIGNAL ;
    PORT
      LAYER M5 ;
        RECT  21.09 126 21.282 130 ;
    END
  END axi_rready_o
  PIN axi_rresp_i[0]
    DIRECTION INPUT ;
    USE SIGNAL ;
    PORT
      LAYER M5 ;
        RECT  21.954 126 22.146 130 ;
    END
  END axi_rresp_i[0]
  PIN axi_rresp_i[1]
    DIRECTION INPUT ;
    USE SIGNAL ;
    PORT
      LAYER M5 ;
        RECT  22.818 126 23.01 130 ;
    END
  END axi_rresp_i[1]
  PIN axi_rvalid_i
    DIRECTION INPUT ;
    USE SIGNAL ;
    PORT
      LAYER M5 ;
        RECT  23.682 126 23.874 130 ;
    END
  END axi_rvalid_i
  PIN axi_wdata_o[0]
    DIRECTION OUTPUT ;
    USE SIGNAL ;
    PORT
      LAYER M5 ;
        RECT  68.61 126 68.802 130 ;
    END
  END axi_wdata_o[0]
  PIN axi_wdata_o[10]
    DIRECTION OUTPUT ;
    USE SIGNAL ;
    PORT
      LAYER M5 ;
        RECT  77.25 126 77.442 130 ;
    END
  END axi_wdata_o[10]
  PIN axi_wdata_o[11]
    DIRECTION OUTPUT ;
    USE SIGNAL ;
    PORT
      LAYER M5 ;
        RECT  78.114 126 78.306 130 ;
    END
  END axi_wdata_o[11]
  PIN axi_wdata_o[12]
    DIRECTION OUTPUT ;
    USE SIGNAL ;
    PORT
      LAYER M5 ;
        RECT  78.978 126 79.17 130 ;
    END
  END axi_wdata_o[12]
  PIN axi_wdata_o[13]
    DIRECTION OUTPUT ;
    USE SIGNAL ;
    PORT
      LAYER M5 ;
        RECT  79.842 126 80.034 130 ;
    END
  END axi_wdata_o[13]
  PIN axi_wdata_o[14]
    DIRECTION OUTPUT ;
    USE SIGNAL ;
    PORT
      LAYER M5 ;
        RECT  80.706 126 80.898 130 ;
    END
  END axi_wdata_o[14]
  PIN axi_wdata_o[15]
    DIRECTION OUTPUT ;
    USE SIGNAL ;
    PORT
      LAYER M5 ;
        RECT  81.57 126 81.762 130 ;
    END
  END axi_wdata_o[15]
  PIN axi_wdata_o[16]
    DIRECTION OUTPUT ;
    USE SIGNAL ;
    PORT
      LAYER M5 ;
        RECT  82.434 126 82.626 130 ;
    END
  END axi_wdata_o[16]
  PIN axi_wdata_o[17]
    DIRECTION OUTPUT ;
    USE SIGNAL ;
    PORT
      LAYER M5 ;
        RECT  83.298 126 83.49 130 ;
    END
  END axi_wdata_o[17]
  PIN axi_wdata_o[18]
    DIRECTION OUTPUT ;
    USE SIGNAL ;
    PORT
      LAYER M5 ;
        RECT  84.162 126 84.354 130 ;
    END
  END axi_wdata_o[18]
  PIN axi_wdata_o[19]
    DIRECTION OUTPUT ;
    USE SIGNAL ;
    PORT
      LAYER M5 ;
        RECT  85.026 126 85.218 130 ;
    END
  END axi_wdata_o[19]
  PIN axi_wdata_o[1]
    DIRECTION OUTPUT ;
    USE SIGNAL ;
    PORT
      LAYER M5 ;
        RECT  69.474 126 69.666 130 ;
    END
  END axi_wdata_o[1]
  PIN axi_wdata_o[20]
    DIRECTION OUTPUT ;
    USE SIGNAL ;
    PORT
      LAYER M5 ;
        RECT  85.89 126 86.082 130 ;
    END
  END axi_wdata_o[20]
  PIN axi_wdata_o[21]
    DIRECTION OUTPUT ;
    USE SIGNAL ;
    PORT
      LAYER M5 ;
        RECT  86.754 126 86.946 130 ;
    END
  END axi_wdata_o[21]
  PIN axi_wdata_o[22]
    DIRECTION OUTPUT ;
    USE SIGNAL ;
    PORT
      LAYER M5 ;
        RECT  87.618 126 87.81 130 ;
    END
  END axi_wdata_o[22]
  PIN axi_wdata_o[23]
    DIRECTION OUTPUT ;
    USE SIGNAL ;
    PORT
      LAYER M5 ;
        RECT  88.482 126 88.674 130 ;
    END
  END axi_wdata_o[23]
  PIN axi_wdata_o[24]
    DIRECTION OUTPUT ;
    USE SIGNAL ;
    PORT
      LAYER M5 ;
        RECT  89.346 126 89.538 130 ;
    END
  END axi_wdata_o[24]
  PIN axi_wdata_o[25]
    DIRECTION OUTPUT ;
    USE SIGNAL ;
    PORT
      LAYER M5 ;
        RECT  90.21 126 90.402 130 ;
    END
  END axi_wdata_o[25]
  PIN axi_wdata_o[26]
    DIRECTION OUTPUT ;
    USE SIGNAL ;
    PORT
      LAYER M5 ;
        RECT  91.074 126 91.266 130 ;
    END
  END axi_wdata_o[26]
  PIN axi_wdata_o[27]
    DIRECTION OUTPUT ;
    USE SIGNAL ;
    PORT
      LAYER M5 ;
        RECT  91.938 126 92.13 130 ;
    END
  END axi_wdata_o[27]
  PIN axi_wdata_o[28]
    DIRECTION OUTPUT ;
    USE SIGNAL ;
    PORT
      LAYER M5 ;
        RECT  92.802 126 92.994 130 ;
    END
  END axi_wdata_o[28]
  PIN axi_wdata_o[29]
    DIRECTION OUTPUT ;
    USE SIGNAL ;
    PORT
      LAYER M5 ;
        RECT  93.666 126 93.858 130 ;
    END
  END axi_wdata_o[29]
  PIN axi_wdata_o[2]
    DIRECTION OUTPUT ;
    USE SIGNAL ;
    PORT
      LAYER M5 ;
        RECT  70.338 126 70.53 130 ;
    END
  END axi_wdata_o[2]
  PIN axi_wdata_o[30]
    DIRECTION OUTPUT ;
    USE SIGNAL ;
    PORT
      LAYER M5 ;
        RECT  94.53 126 94.722 130 ;
    END
  END axi_wdata_o[30]
  PIN axi_wdata_o[31]
    DIRECTION OUTPUT ;
    USE SIGNAL ;
    PORT
      LAYER M5 ;
        RECT  95.394 126 95.586 130 ;
    END
  END axi_wdata_o[31]
  PIN axi_wdata_o[3]
    DIRECTION OUTPUT ;
    USE SIGNAL ;
    PORT
      LAYER M5 ;
        RECT  71.202 126 71.394 130 ;
    END
  END axi_wdata_o[3]
  PIN axi_wdata_o[4]
    DIRECTION OUTPUT ;
    USE SIGNAL ;
    PORT
      LAYER M5 ;
        RECT  72.066 126 72.258 130 ;
    END
  END axi_wdata_o[4]
  PIN axi_wdata_o[5]
    DIRECTION OUTPUT ;
    USE SIGNAL ;
    PORT
      LAYER M5 ;
        RECT  72.93 126 73.122 130 ;
    END
  END axi_wdata_o[5]
  PIN axi_wdata_o[6]
    DIRECTION OUTPUT ;
    USE SIGNAL ;
    PORT
      LAYER M5 ;
        RECT  73.794 126 73.986 130 ;
    END
  END axi_wdata_o[6]
  PIN axi_wdata_o[7]
    DIRECTION OUTPUT ;
    USE SIGNAL ;
    PORT
      LAYER M5 ;
        RECT  74.658 126 74.85 130 ;
    END
  END axi_wdata_o[7]
  PIN axi_wdata_o[8]
    DIRECTION OUTPUT ;
    USE SIGNAL ;
    PORT
      LAYER M5 ;
        RECT  75.522 126 75.714 130 ;
    END
  END axi_wdata_o[8]
  PIN axi_wdata_o[9]
    DIRECTION OUTPUT ;
    USE SIGNAL ;
    PORT
      LAYER M5 ;
        RECT  76.386 126 76.578 130 ;
    END
  END axi_wdata_o[9]
  PIN axi_wlast_o
    DIRECTION OUTPUT ;
    USE SIGNAL ;
    PORT
      LAYER M5 ;
        RECT  96.258 126 96.45 130 ;
    END
  END axi_wlast_o
  PIN axi_wready_i
    DIRECTION INPUT ;
    USE SIGNAL ;
    PORT
      LAYER M5 ;
        RECT  97.122 126 97.314 130 ;
    END
  END axi_wready_i
  PIN axi_wstrb_o[0]
    DIRECTION OUTPUT ;
    USE SIGNAL ;
    PORT
      LAYER M5 ;
        RECT  97.986 126 98.178 130 ;
    END
  END axi_wstrb_o[0]
  PIN axi_wstrb_o[1]
    DIRECTION OUTPUT ;
    USE SIGNAL ;
    PORT
      LAYER M5 ;
        RECT  98.85 126 99.042 130 ;
    END
  END axi_wstrb_o[1]
  PIN axi_wstrb_o[2]
    DIRECTION OUTPUT ;
    USE SIGNAL ;
    PORT
      LAYER M5 ;
        RECT  99.714 126 99.906 130 ;
    END
  END axi_wstrb_o[2]
  PIN axi_wstrb_o[3]
    DIRECTION OUTPUT ;
    USE SIGNAL ;
    PORT
      LAYER M5 ;
        RECT  100.578 126 100.77 130 ;
    END
  END axi_wstrb_o[3]
  PIN axi_wvalid_o
    DIRECTION OUTPUT ;
    USE SIGNAL ;
    PORT
      LAYER M5 ;
        RECT  101.442 126 101.634 130 ;
    END
  END axi_wvalid_o
  PIN clk_i
    DIRECTION INPUT ;
    USE SIGNAL ;
    PORT
      LAYER M5 ;
        RECT  4.242 0 4.434 4 ;
    END
  END clk_i
  PIN commit_insn_o[0]
    DIRECTION OUTPUT ;
    USE SIGNAL ;
    PORT
      LAYER M5 ;
        RECT  102.306 126 102.498 130 ;
    END
  END commit_insn_o[0]
  PIN commit_insn_o[10]
    DIRECTION OUTPUT ;
    USE SIGNAL ;
    PORT
      LAYER M5 ;
        RECT  110.946 126 111.138 130 ;
    END
  END commit_insn_o[10]
  PIN commit_insn_o[11]
    DIRECTION OUTPUT ;
    USE SIGNAL ;
    PORT
      LAYER M5 ;
        RECT  111.81 126 112.002 130 ;
    END
  END commit_insn_o[11]
  PIN commit_insn_o[12]
    DIRECTION OUTPUT ;
    USE SIGNAL ;
    PORT
      LAYER M5 ;
        RECT  112.674 126 112.866 130 ;
    END
  END commit_insn_o[12]
  PIN commit_insn_o[13]
    DIRECTION OUTPUT ;
    USE SIGNAL ;
    PORT
      LAYER M5 ;
        RECT  113.538 126 113.73 130 ;
    END
  END commit_insn_o[13]
  PIN commit_insn_o[14]
    DIRECTION OUTPUT ;
    USE SIGNAL ;
    PORT
      LAYER M5 ;
        RECT  114.402 126 114.594 130 ;
    END
  END commit_insn_o[14]
  PIN commit_insn_o[15]
    DIRECTION OUTPUT ;
    USE SIGNAL ;
    PORT
      LAYER M5 ;
        RECT  115.266 126 115.458 130 ;
    END
  END commit_insn_o[15]
  PIN commit_insn_o[16]
    DIRECTION OUTPUT ;
    USE SIGNAL ;
    PORT
      LAYER M5 ;
        RECT  116.13 126 116.322 130 ;
    END
  END commit_insn_o[16]
  PIN commit_insn_o[17]
    DIRECTION OUTPUT ;
    USE SIGNAL ;
    PORT
      LAYER M5 ;
        RECT  116.994 126 117.186 130 ;
    END
  END commit_insn_o[17]
  PIN commit_insn_o[18]
    DIRECTION OUTPUT ;
    USE SIGNAL ;
    PORT
      LAYER M5 ;
        RECT  117.858 126 118.05 130 ;
    END
  END commit_insn_o[18]
  PIN commit_insn_o[19]
    DIRECTION OUTPUT ;
    USE SIGNAL ;
    PORT
      LAYER M5 ;
        RECT  118.722 126 118.914 130 ;
    END
  END commit_insn_o[19]
  PIN commit_insn_o[1]
    DIRECTION OUTPUT ;
    USE SIGNAL ;
    PORT
      LAYER M5 ;
        RECT  103.17 126 103.362 130 ;
    END
  END commit_insn_o[1]
  PIN commit_insn_o[20]
    DIRECTION OUTPUT ;
    USE SIGNAL ;
    PORT
      LAYER M4 ;
        RECT  126 80.706 130 80.898 ;
    END
  END commit_insn_o[20]
  PIN commit_insn_o[21]
    DIRECTION OUTPUT ;
    USE SIGNAL ;
    PORT
      LAYER M4 ;
        RECT  126 81.57 130 81.762 ;
    END
  END commit_insn_o[21]
  PIN commit_insn_o[22]
    DIRECTION OUTPUT ;
    USE SIGNAL ;
    PORT
      LAYER M4 ;
        RECT  126 82.434 130 82.626 ;
    END
  END commit_insn_o[22]
  PIN commit_insn_o[23]
    DIRECTION OUTPUT ;
    USE SIGNAL ;
    PORT
      LAYER M4 ;
        RECT  126 83.298 130 83.49 ;
    END
  END commit_insn_o[23]
  PIN commit_insn_o[24]
    DIRECTION OUTPUT ;
    USE SIGNAL ;
    PORT
      LAYER M4 ;
        RECT  126 84.162 130 84.354 ;
    END
  END commit_insn_o[24]
  PIN commit_insn_o[25]
    DIRECTION OUTPUT ;
    USE SIGNAL ;
    PORT
      LAYER M4 ;
        RECT  126 85.026 130 85.218 ;
    END
  END commit_insn_o[25]
  PIN commit_insn_o[26]
    DIRECTION OUTPUT ;
    USE SIGNAL ;
    PORT
      LAYER M4 ;
        RECT  126 85.89 130 86.082 ;
    END
  END commit_insn_o[26]
  PIN commit_insn_o[27]
    DIRECTION OUTPUT ;
    USE SIGNAL ;
    PORT
      LAYER M4 ;
        RECT  126 86.754 130 86.946 ;
    END
  END commit_insn_o[27]
  PIN commit_insn_o[28]
    DIRECTION OUTPUT ;
    USE SIGNAL ;
    PORT
      LAYER M4 ;
        RECT  126 87.618 130 87.81 ;
    END
  END commit_insn_o[28]
  PIN commit_insn_o[29]
    DIRECTION OUTPUT ;
    USE SIGNAL ;
    PORT
      LAYER M4 ;
        RECT  126 88.482 130 88.674 ;
    END
  END commit_insn_o[29]
  PIN commit_insn_o[2]
    DIRECTION OUTPUT ;
    USE SIGNAL ;
    PORT
      LAYER M5 ;
        RECT  104.034 126 104.226 130 ;
    END
  END commit_insn_o[2]
  PIN commit_insn_o[30]
    DIRECTION OUTPUT ;
    USE SIGNAL ;
    PORT
      LAYER M4 ;
        RECT  126 89.346 130 89.538 ;
    END
  END commit_insn_o[30]
  PIN commit_insn_o[31]
    DIRECTION OUTPUT ;
    USE SIGNAL ;
    PORT
      LAYER M4 ;
        RECT  126 90.21 130 90.402 ;
    END
  END commit_insn_o[31]
  PIN commit_insn_o[3]
    DIRECTION OUTPUT ;
    USE SIGNAL ;
    PORT
      LAYER M5 ;
        RECT  104.898 126 105.09 130 ;
    END
  END commit_insn_o[3]
  PIN commit_insn_o[4]
    DIRECTION OUTPUT ;
    USE SIGNAL ;
    PORT
      LAYER M5 ;
        RECT  105.762 126 105.954 130 ;
    END
  END commit_insn_o[4]
  PIN commit_insn_o[5]
    DIRECTION OUTPUT ;
    USE SIGNAL ;
    PORT
      LAYER M5 ;
        RECT  106.626 126 106.818 130 ;
    END
  END commit_insn_o[5]
  PIN commit_insn_o[6]
    DIRECTION OUTPUT ;
    USE SIGNAL ;
    PORT
      LAYER M5 ;
        RECT  107.49 126 107.682 130 ;
    END
  END commit_insn_o[6]
  PIN commit_insn_o[7]
    DIRECTION OUTPUT ;
    USE SIGNAL ;
    PORT
      LAYER M5 ;
        RECT  108.354 126 108.546 130 ;
    END
  END commit_insn_o[7]
  PIN commit_insn_o[8]
    DIRECTION OUTPUT ;
    USE SIGNAL ;
    PORT
      LAYER M5 ;
        RECT  109.218 126 109.41 130 ;
    END
  END commit_insn_o[8]
  PIN commit_insn_o[9]
    DIRECTION OUTPUT ;
    USE SIGNAL ;
    PORT
      LAYER M5 ;
        RECT  110.082 126 110.274 130 ;
    END
  END commit_insn_o[9]
  PIN commit_pc_o[0]
    DIRECTION OUTPUT ;
    USE SIGNAL ;
    PORT
      LAYER M4 ;
        RECT  126 91.074 130 91.266 ;
    END
  END commit_pc_o[0]
  PIN commit_pc_o[10]
    DIRECTION OUTPUT ;
    USE SIGNAL ;
    PORT
      LAYER M4 ;
        RECT  126 99.714 130 99.906 ;
    END
  END commit_pc_o[10]
  PIN commit_pc_o[11]
    DIRECTION OUTPUT ;
    USE SIGNAL ;
    PORT
      LAYER M4 ;
        RECT  126 100.578 130 100.77 ;
    END
  END commit_pc_o[11]
  PIN commit_pc_o[12]
    DIRECTION OUTPUT ;
    USE SIGNAL ;
    PORT
      LAYER M4 ;
        RECT  126 101.442 130 101.634 ;
    END
  END commit_pc_o[12]
  PIN commit_pc_o[13]
    DIRECTION OUTPUT ;
    USE SIGNAL ;
    PORT
      LAYER M4 ;
        RECT  126 102.306 130 102.498 ;
    END
  END commit_pc_o[13]
  PIN commit_pc_o[14]
    DIRECTION OUTPUT ;
    USE SIGNAL ;
    PORT
      LAYER M4 ;
        RECT  126 103.17 130 103.362 ;
    END
  END commit_pc_o[14]
  PIN commit_pc_o[15]
    DIRECTION OUTPUT ;
    USE SIGNAL ;
    PORT
      LAYER M4 ;
        RECT  126 104.034 130 104.226 ;
    END
  END commit_pc_o[15]
  PIN commit_pc_o[16]
    DIRECTION OUTPUT ;
    USE SIGNAL ;
    PORT
      LAYER M4 ;
        RECT  126 104.898 130 105.09 ;
    END
  END commit_pc_o[16]
  PIN commit_pc_o[17]
    DIRECTION OUTPUT ;
    USE SIGNAL ;
    PORT
      LAYER M4 ;
        RECT  126 105.762 130 105.954 ;
    END
  END commit_pc_o[17]
  PIN commit_pc_o[18]
    DIRECTION OUTPUT ;
    USE SIGNAL ;
    PORT
      LAYER M4 ;
        RECT  126 106.626 130 106.818 ;
    END
  END commit_pc_o[18]
  PIN commit_pc_o[19]
    DIRECTION OUTPUT ;
    USE SIGNAL ;
    PORT
      LAYER M4 ;
        RECT  126 107.49 130 107.682 ;
    END
  END commit_pc_o[19]
  PIN commit_pc_o[1]
    DIRECTION OUTPUT ;
    USE SIGNAL ;
    PORT
      LAYER M4 ;
        RECT  126 91.938 130 92.13 ;
    END
  END commit_pc_o[1]
  PIN commit_pc_o[20]
    DIRECTION OUTPUT ;
    USE SIGNAL ;
    PORT
      LAYER M4 ;
        RECT  126 108.354 130 108.546 ;
    END
  END commit_pc_o[20]
  PIN commit_pc_o[21]
    DIRECTION OUTPUT ;
    USE SIGNAL ;
    PORT
      LAYER M4 ;
        RECT  126 109.218 130 109.41 ;
    END
  END commit_pc_o[21]
  PIN commit_pc_o[22]
    DIRECTION OUTPUT ;
    USE SIGNAL ;
    PORT
      LAYER M4 ;
        RECT  126 110.082 130 110.274 ;
    END
  END commit_pc_o[22]
  PIN commit_pc_o[23]
    DIRECTION OUTPUT ;
    USE SIGNAL ;
    PORT
      LAYER M4 ;
        RECT  126 110.946 130 111.138 ;
    END
  END commit_pc_o[23]
  PIN commit_pc_o[24]
    DIRECTION OUTPUT ;
    USE SIGNAL ;
    PORT
      LAYER M4 ;
        RECT  126 111.81 130 112.002 ;
    END
  END commit_pc_o[24]
  PIN commit_pc_o[25]
    DIRECTION OUTPUT ;
    USE SIGNAL ;
    PORT
      LAYER M4 ;
        RECT  126 112.674 130 112.866 ;
    END
  END commit_pc_o[25]
  PIN commit_pc_o[26]
    DIRECTION OUTPUT ;
    USE SIGNAL ;
    PORT
      LAYER M4 ;
        RECT  126 113.538 130 113.73 ;
    END
  END commit_pc_o[26]
  PIN commit_pc_o[27]
    DIRECTION OUTPUT ;
    USE SIGNAL ;
    PORT
      LAYER M4 ;
        RECT  126 114.402 130 114.594 ;
    END
  END commit_pc_o[27]
  PIN commit_pc_o[28]
    DIRECTION OUTPUT ;
    USE SIGNAL ;
    PORT
      LAYER M4 ;
        RECT  126 115.266 130 115.458 ;
    END
  END commit_pc_o[28]
  PIN commit_pc_o[29]
    DIRECTION OUTPUT ;
    USE SIGNAL ;
    PORT
      LAYER M4 ;
        RECT  126 116.13 130 116.322 ;
    END
  END commit_pc_o[29]
  PIN commit_pc_o[2]
    DIRECTION OUTPUT ;
    USE SIGNAL ;
    PORT
      LAYER M4 ;
        RECT  126 92.802 130 92.994 ;
    END
  END commit_pc_o[2]
  PIN commit_pc_o[30]
    DIRECTION OUTPUT ;
    USE SIGNAL ;
    PORT
      LAYER M4 ;
        RECT  126 116.994 130 117.186 ;
    END
  END commit_pc_o[30]
  PIN commit_pc_o[31]
    DIRECTION OUTPUT ;
    USE SIGNAL ;
    PORT
      LAYER M4 ;
        RECT  126 117.858 130 118.05 ;
    END
  END commit_pc_o[31]
  PIN commit_pc_o[3]
    DIRECTION OUTPUT ;
    USE SIGNAL ;
    PORT
      LAYER M4 ;
        RECT  126 93.666 130 93.858 ;
    END
  END commit_pc_o[3]
  PIN commit_pc_o[4]
    DIRECTION OUTPUT ;
    USE SIGNAL ;
    PORT
      LAYER M4 ;
        RECT  126 94.53 130 94.722 ;
    END
  END commit_pc_o[4]
  PIN commit_pc_o[5]
    DIRECTION OUTPUT ;
    USE SIGNAL ;
    PORT
      LAYER M4 ;
        RECT  126 95.394 130 95.586 ;
    END
  END commit_pc_o[5]
  PIN commit_pc_o[6]
    DIRECTION OUTPUT ;
    USE SIGNAL ;
    PORT
      LAYER M4 ;
        RECT  126 96.258 130 96.45 ;
    END
  END commit_pc_o[6]
  PIN commit_pc_o[7]
    DIRECTION OUTPUT ;
    USE SIGNAL ;
    PORT
      LAYER M4 ;
        RECT  126 97.122 130 97.314 ;
    END
  END commit_pc_o[7]
  PIN commit_pc_o[8]
    DIRECTION OUTPUT ;
    USE SIGNAL ;
    PORT
      LAYER M4 ;
        RECT  126 97.986 130 98.178 ;
    END
  END commit_pc_o[8]
  PIN commit_pc_o[9]
    DIRECTION OUTPUT ;
    USE SIGNAL ;
    PORT
      LAYER M4 ;
        RECT  126 98.85 130 99.042 ;
    END
  END commit_pc_o[9]
  PIN commit_valid_o
    DIRECTION OUTPUT ;
    USE SIGNAL ;
    PORT
      LAYER M4 ;
        RECT  126 118.722 130 118.914 ;
    END
  END commit_valid_o
  PIN debug_branch_taken_o
    DIRECTION OUTPUT ;
    USE SIGNAL ;
    PORT
      LAYER M5 ;
        RECT  10.29 0 10.482 4 ;
    END
  END debug_branch_taken_o
  PIN debug_ebreak_o
    DIRECTION OUTPUT ;
    USE SIGNAL ;
    PORT
      LAYER M5 ;
        RECT  11.802 0 11.994 4 ;
    END
  END debug_ebreak_o
  PIN debug_pc_src_o
    DIRECTION OUTPUT ;
    USE SIGNAL ;
    PORT
      LAYER M5 ;
        RECT  13.314 0 13.506 4 ;
    END
  END debug_pc_src_o
  PIN debug_rs1_data_o[0]
    DIRECTION OUTPUT ;
    USE SIGNAL ;
    PORT
      LAYER M5 ;
        RECT  14.826 0 15.018 4 ;
    END
  END debug_rs1_data_o[0]
  PIN debug_rs1_data_o[10]
    DIRECTION OUTPUT ;
    USE SIGNAL ;
    PORT
      LAYER M5 ;
        RECT  29.946 0 30.138 4 ;
    END
  END debug_rs1_data_o[10]
  PIN debug_rs1_data_o[11]
    DIRECTION OUTPUT ;
    USE SIGNAL ;
    PORT
      LAYER M5 ;
        RECT  31.458 0 31.65 4 ;
    END
  END debug_rs1_data_o[11]
  PIN debug_rs1_data_o[12]
    DIRECTION OUTPUT ;
    USE SIGNAL ;
    PORT
      LAYER M5 ;
        RECT  32.97 0 33.162 4 ;
    END
  END debug_rs1_data_o[12]
  PIN debug_rs1_data_o[13]
    DIRECTION OUTPUT ;
    USE SIGNAL ;
    PORT
      LAYER M5 ;
        RECT  34.482 0 34.674 4 ;
    END
  END debug_rs1_data_o[13]
  PIN debug_rs1_data_o[14]
    DIRECTION OUTPUT ;
    USE SIGNAL ;
    PORT
      LAYER M5 ;
        RECT  35.994 0 36.186 4 ;
    END
  END debug_rs1_data_o[14]
  PIN debug_rs1_data_o[15]
    DIRECTION OUTPUT ;
    USE SIGNAL ;
    PORT
      LAYER M5 ;
        RECT  37.506 0 37.698 4 ;
    END
  END debug_rs1_data_o[15]
  PIN debug_rs1_data_o[16]
    DIRECTION OUTPUT ;
    USE SIGNAL ;
    PORT
      LAYER M5 ;
        RECT  39.018 0 39.21 4 ;
    END
  END debug_rs1_data_o[16]
  PIN debug_rs1_data_o[17]
    DIRECTION OUTPUT ;
    USE SIGNAL ;
    PORT
      LAYER M5 ;
        RECT  40.53 0 40.722 4 ;
    END
  END debug_rs1_data_o[17]
  PIN debug_rs1_data_o[18]
    DIRECTION OUTPUT ;
    USE SIGNAL ;
    PORT
      LAYER M5 ;
        RECT  42.042 0 42.234 4 ;
    END
  END debug_rs1_data_o[18]
  PIN debug_rs1_data_o[19]
    DIRECTION OUTPUT ;
    USE SIGNAL ;
    PORT
      LAYER M5 ;
        RECT  43.554 0 43.746 4 ;
    END
  END debug_rs1_data_o[19]
  PIN debug_rs1_data_o[1]
    DIRECTION OUTPUT ;
    USE SIGNAL ;
    PORT
      LAYER M5 ;
        RECT  16.338 0 16.53 4 ;
    END
  END debug_rs1_data_o[1]
  PIN debug_rs1_data_o[20]
    DIRECTION OUTPUT ;
    USE SIGNAL ;
    PORT
      LAYER M5 ;
        RECT  45.066 0 45.258 4 ;
    END
  END debug_rs1_data_o[20]
  PIN debug_rs1_data_o[21]
    DIRECTION OUTPUT ;
    USE SIGNAL ;
    PORT
      LAYER M5 ;
        RECT  46.578 0 46.77 4 ;
    END
  END debug_rs1_data_o[21]
  PIN debug_rs1_data_o[22]
    DIRECTION OUTPUT ;
    USE SIGNAL ;
    PORT
      LAYER M5 ;
        RECT  48.09 0 48.282 4 ;
    END
  END debug_rs1_data_o[22]
  PIN debug_rs1_data_o[23]
    DIRECTION OUTPUT ;
    USE SIGNAL ;
    PORT
      LAYER M5 ;
        RECT  49.602 0 49.794 4 ;
    END
  END debug_rs1_data_o[23]
  PIN debug_rs1_data_o[24]
    DIRECTION OUTPUT ;
    USE SIGNAL ;
    PORT
      LAYER M5 ;
        RECT  51.114 0 51.306 4 ;
    END
  END debug_rs1_data_o[24]
  PIN debug_rs1_data_o[25]
    DIRECTION OUTPUT ;
    USE SIGNAL ;
    PORT
      LAYER M5 ;
        RECT  52.626 0 52.818 4 ;
    END
  END debug_rs1_data_o[25]
  PIN debug_rs1_data_o[26]
    DIRECTION OUTPUT ;
    USE SIGNAL ;
    PORT
      LAYER M5 ;
        RECT  54.138 0 54.33 4 ;
    END
  END debug_rs1_data_o[26]
  PIN debug_rs1_data_o[27]
    DIRECTION OUTPUT ;
    USE SIGNAL ;
    PORT
      LAYER M5 ;
        RECT  55.65 0 55.842 4 ;
    END
  END debug_rs1_data_o[27]
  PIN debug_rs1_data_o[28]
    DIRECTION OUTPUT ;
    USE SIGNAL ;
    PORT
      LAYER M5 ;
        RECT  57.162 0 57.354 4 ;
    END
  END debug_rs1_data_o[28]
  PIN debug_rs1_data_o[29]
    DIRECTION OUTPUT ;
    USE SIGNAL ;
    PORT
      LAYER M5 ;
        RECT  58.674 0 58.866 4 ;
    END
  END debug_rs1_data_o[29]
  PIN debug_rs1_data_o[2]
    DIRECTION OUTPUT ;
    USE SIGNAL ;
    PORT
      LAYER M5 ;
        RECT  17.85 0 18.042 4 ;
    END
  END debug_rs1_data_o[2]
  PIN debug_rs1_data_o[30]
    DIRECTION OUTPUT ;
    USE SIGNAL ;
    PORT
      LAYER M5 ;
        RECT  60.186 0 60.378 4 ;
    END
  END debug_rs1_data_o[30]
  PIN debug_rs1_data_o[31]
    DIRECTION OUTPUT ;
    USE SIGNAL ;
    PORT
      LAYER M5 ;
        RECT  61.698 0 61.89 4 ;
    END
  END debug_rs1_data_o[31]
  PIN debug_rs1_data_o[3]
    DIRECTION OUTPUT ;
    USE SIGNAL ;
    PORT
      LAYER M5 ;
        RECT  19.362 0 19.554 4 ;
    END
  END debug_rs1_data_o[3]
  PIN debug_rs1_data_o[4]
    DIRECTION OUTPUT ;
    USE SIGNAL ;
    PORT
      LAYER M5 ;
        RECT  20.874 0 21.066 4 ;
    END
  END debug_rs1_data_o[4]
  PIN debug_rs1_data_o[5]
    DIRECTION OUTPUT ;
    USE SIGNAL ;
    PORT
      LAYER M5 ;
        RECT  22.386 0 22.578 4 ;
    END
  END debug_rs1_data_o[5]
  PIN debug_rs1_data_o[6]
    DIRECTION OUTPUT ;
    USE SIGNAL ;
    PORT
      LAYER M5 ;
        RECT  23.898 0 24.09 4 ;
    END
  END debug_rs1_data_o[6]
  PIN debug_rs1_data_o[7]
    DIRECTION OUTPUT ;
    USE SIGNAL ;
    PORT
      LAYER M5 ;
        RECT  25.41 0 25.602 4 ;
    END
  END debug_rs1_data_o[7]
  PIN debug_rs1_data_o[8]
    DIRECTION OUTPUT ;
    USE SIGNAL ;
    PORT
      LAYER M5 ;
        RECT  26.922 0 27.114 4 ;
    END
  END debug_rs1_data_o[8]
  PIN debug_rs1_data_o[9]
    DIRECTION OUTPUT ;
    USE SIGNAL ;
    PORT
      LAYER M5 ;
        RECT  28.434 0 28.626 4 ;
    END
  END debug_rs1_data_o[9]
  PIN debug_rs2_data_o[0]
    DIRECTION OUTPUT ;
    USE SIGNAL ;
    PORT
      LAYER M5 ;
        RECT  63.21 0 63.402 4 ;
    END
  END debug_rs2_data_o[0]
  PIN debug_rs2_data_o[10]
    DIRECTION OUTPUT ;
    USE SIGNAL ;
    PORT
      LAYER M5 ;
        RECT  78.33 0 78.522 4 ;
    END
  END debug_rs2_data_o[10]
  PIN debug_rs2_data_o[11]
    DIRECTION OUTPUT ;
    USE SIGNAL ;
    PORT
      LAYER M5 ;
        RECT  79.842 0 80.034 4 ;
    END
  END debug_rs2_data_o[11]
  PIN debug_rs2_data_o[12]
    DIRECTION OUTPUT ;
    USE SIGNAL ;
    PORT
      LAYER M5 ;
        RECT  81.354 0 81.546 4 ;
    END
  END debug_rs2_data_o[12]
  PIN debug_rs2_data_o[13]
    DIRECTION OUTPUT ;
    USE SIGNAL ;
    PORT
      LAYER M5 ;
        RECT  82.866 0 83.058 4 ;
    END
  END debug_rs2_data_o[13]
  PIN debug_rs2_data_o[14]
    DIRECTION OUTPUT ;
    USE SIGNAL ;
    PORT
      LAYER M5 ;
        RECT  84.378 0 84.57 4 ;
    END
  END debug_rs2_data_o[14]
  PIN debug_rs2_data_o[15]
    DIRECTION OUTPUT ;
    USE SIGNAL ;
    PORT
      LAYER M5 ;
        RECT  85.89 0 86.082 4 ;
    END
  END debug_rs2_data_o[15]
  PIN debug_rs2_data_o[16]
    DIRECTION OUTPUT ;
    USE SIGNAL ;
    PORT
      LAYER M5 ;
        RECT  87.402 0 87.594 4 ;
    END
  END debug_rs2_data_o[16]
  PIN debug_rs2_data_o[17]
    DIRECTION OUTPUT ;
    USE SIGNAL ;
    PORT
      LAYER M5 ;
        RECT  88.914 0 89.106 4 ;
    END
  END debug_rs2_data_o[17]
  PIN debug_rs2_data_o[18]
    DIRECTION OUTPUT ;
    USE SIGNAL ;
    PORT
      LAYER M5 ;
        RECT  90.426 0 90.618 4 ;
    END
  END debug_rs2_data_o[18]
  PIN debug_rs2_data_o[19]
    DIRECTION OUTPUT ;
    USE SIGNAL ;
    PORT
      LAYER M5 ;
        RECT  91.938 0 92.13 4 ;
    END
  END debug_rs2_data_o[19]
  PIN debug_rs2_data_o[1]
    DIRECTION OUTPUT ;
    USE SIGNAL ;
    PORT
      LAYER M5 ;
        RECT  64.722 0 64.914 4 ;
    END
  END debug_rs2_data_o[1]
  PIN debug_rs2_data_o[20]
    DIRECTION OUTPUT ;
    USE SIGNAL ;
    PORT
      LAYER M5 ;
        RECT  93.45 0 93.642 4 ;
    END
  END debug_rs2_data_o[20]
  PIN debug_rs2_data_o[21]
    DIRECTION OUTPUT ;
    USE SIGNAL ;
    PORT
      LAYER M5 ;
        RECT  94.962 0 95.154 4 ;
    END
  END debug_rs2_data_o[21]
  PIN debug_rs2_data_o[22]
    DIRECTION OUTPUT ;
    USE SIGNAL ;
    PORT
      LAYER M5 ;
        RECT  96.474 0 96.666 4 ;
    END
  END debug_rs2_data_o[22]
  PIN debug_rs2_data_o[23]
    DIRECTION OUTPUT ;
    USE SIGNAL ;
    PORT
      LAYER M5 ;
        RECT  97.986 0 98.178 4 ;
    END
  END debug_rs2_data_o[23]
  PIN debug_rs2_data_o[24]
    DIRECTION OUTPUT ;
    USE SIGNAL ;
    PORT
      LAYER M5 ;
        RECT  99.498 0 99.69 4 ;
    END
  END debug_rs2_data_o[24]
  PIN debug_rs2_data_o[25]
    DIRECTION OUTPUT ;
    USE SIGNAL ;
    PORT
      LAYER M5 ;
        RECT  101.01 0 101.202 4 ;
    END
  END debug_rs2_data_o[25]
  PIN debug_rs2_data_o[26]
    DIRECTION OUTPUT ;
    USE SIGNAL ;
    PORT
      LAYER M5 ;
        RECT  102.522 0 102.714 4 ;
    END
  END debug_rs2_data_o[26]
  PIN debug_rs2_data_o[27]
    DIRECTION OUTPUT ;
    USE SIGNAL ;
    PORT
      LAYER M5 ;
        RECT  104.034 0 104.226 4 ;
    END
  END debug_rs2_data_o[27]
  PIN debug_rs2_data_o[28]
    DIRECTION OUTPUT ;
    USE SIGNAL ;
    PORT
      LAYER M5 ;
        RECT  105.546 0 105.738 4 ;
    END
  END debug_rs2_data_o[28]
  PIN debug_rs2_data_o[29]
    DIRECTION OUTPUT ;
    USE SIGNAL ;
    PORT
      LAYER M5 ;
        RECT  107.058 0 107.25 4 ;
    END
  END debug_rs2_data_o[29]
  PIN debug_rs2_data_o[2]
    DIRECTION OUTPUT ;
    USE SIGNAL ;
    PORT
      LAYER M5 ;
        RECT  66.234 0 66.426 4 ;
    END
  END debug_rs2_data_o[2]
  PIN debug_rs2_data_o[30]
    DIRECTION OUTPUT ;
    USE SIGNAL ;
    PORT
      LAYER M5 ;
        RECT  108.57 0 108.762 4 ;
    END
  END debug_rs2_data_o[30]
  PIN debug_rs2_data_o[31]
    DIRECTION OUTPUT ;
    USE SIGNAL ;
    PORT
      LAYER M5 ;
        RECT  110.082 0 110.274 4 ;
    END
  END debug_rs2_data_o[31]
  PIN debug_rs2_data_o[3]
    DIRECTION OUTPUT ;
    USE SIGNAL ;
    PORT
      LAYER M5 ;
        RECT  67.746 0 67.938 4 ;
    END
  END debug_rs2_data_o[3]
  PIN debug_rs2_data_o[4]
    DIRECTION OUTPUT ;
    USE SIGNAL ;
    PORT
      LAYER M5 ;
        RECT  69.258 0 69.45 4 ;
    END
  END debug_rs2_data_o[4]
  PIN debug_rs2_data_o[5]
    DIRECTION OUTPUT ;
    USE SIGNAL ;
    PORT
      LAYER M5 ;
        RECT  70.77 0 70.962 4 ;
    END
  END debug_rs2_data_o[5]
  PIN debug_rs2_data_o[6]
    DIRECTION OUTPUT ;
    USE SIGNAL ;
    PORT
      LAYER M5 ;
        RECT  72.282 0 72.474 4 ;
    END
  END debug_rs2_data_o[6]
  PIN debug_rs2_data_o[7]
    DIRECTION OUTPUT ;
    USE SIGNAL ;
    PORT
      LAYER M5 ;
        RECT  73.794 0 73.986 4 ;
    END
  END debug_rs2_data_o[7]
  PIN debug_rs2_data_o[8]
    DIRECTION OUTPUT ;
    USE SIGNAL ;
    PORT
      LAYER M5 ;
        RECT  75.306 0 75.498 4 ;
    END
  END debug_rs2_data_o[8]
  PIN debug_rs2_data_o[9]
    DIRECTION OUTPUT ;
    USE SIGNAL ;
    PORT
      LAYER M5 ;
        RECT  76.818 0 77.01 4 ;
    END
  END debug_rs2_data_o[9]
  PIN debug_state_o[0]
    DIRECTION OUTPUT ;
    USE SIGNAL ;
    PORT
      LAYER M5 ;
        RECT  111.594 0 111.786 4 ;
    END
  END debug_state_o[0]
  PIN debug_state_o[1]
    DIRECTION OUTPUT ;
    USE SIGNAL ;
    PORT
      LAYER M5 ;
        RECT  113.106 0 113.298 4 ;
    END
  END debug_state_o[1]
  PIN debug_state_o[2]
    DIRECTION OUTPUT ;
    USE SIGNAL ;
    PORT
      LAYER M5 ;
        RECT  114.618 0 114.81 4 ;
    END
  END debug_state_o[2]
  PIN debug_state_o[3]
    DIRECTION OUTPUT ;
    USE SIGNAL ;
    PORT
      LAYER M5 ;
        RECT  116.13 0 116.322 4 ;
    END
  END debug_state_o[3]
  PIN debug_take_branch_jump_o
    DIRECTION OUTPUT ;
    USE SIGNAL ;
    PORT
      LAYER M5 ;
        RECT  117.642 0 117.834 4 ;
    END
  END debug_take_branch_jump_o
  PIN ext_irq_i
    DIRECTION INPUT ;
    USE SIGNAL ;
    PORT
      LAYER M5 ;
        RECT  7.266 0 7.458 4 ;
    END
  END ext_irq_i
  PIN rst_n_i
    DIRECTION INPUT ;
    USE SIGNAL ;
    PORT
      LAYER M5 ;
        RECT  5.754 0 5.946 4 ;
    END
  END rst_n_i
  PIN timer_irq_i
    DIRECTION INPUT ;
    USE SIGNAL ;
    PORT
      LAYER M5 ;
        RECT  8.778 0 8.97 4 ;
    END
  END timer_irq_i
  PIN trap_cause_o[0]
    DIRECTION OUTPUT ;
    USE SIGNAL ;
    PORT
      LAYER M5 ;
        RECT  119.154 0 119.346 4 ;
    END
  END trap_cause_o[0]
  PIN trap_cause_o[1]
    DIRECTION OUTPUT ;
    USE SIGNAL ;
    PORT
      LAYER M5 ;
        RECT  120.666 0 120.858 4 ;
    END
  END trap_cause_o[1]
  PIN trap_cause_o[2]
    DIRECTION OUTPUT ;
    USE SIGNAL ;
    PORT
      LAYER M5 ;
        RECT  122.178 0 122.37 4 ;
    END
  END trap_cause_o[2]
  PIN trap_cause_o[3]
    DIRECTION OUTPUT ;
    USE SIGNAL ;
    PORT
      LAYER M5 ;
        RECT  123.69 0 123.882 4 ;
    END
  END trap_cause_o[3]
  PIN trap_taken_o
    DIRECTION OUTPUT ;
    USE SIGNAL ;
    PORT
      LAYER M5 ;
        RECT  125.202 0 125.394 4 ;
    END
  END trap_taken_o
  OBS
    LAYER M1 ;
     RECT  0 0 130 130 ;
    LAYER M2 ;
     RECT  0 0 130 130 ;
    LAYER M3 ;
     RECT  0 0 130 130 ;
    LAYER M4 ;
     RECT  0 0 130 130 ;
  END
END rv32i_cpu_top
END LIBRARY
